# tiny_counter abstract. Synthetic test fixture.
VERSION 5.8 ;
BUSBITCHARS "[]" ;
DIVIDERCHAR "/" ;
UNITS
  DATABASE MICRONS 1000 ;
END UNITS
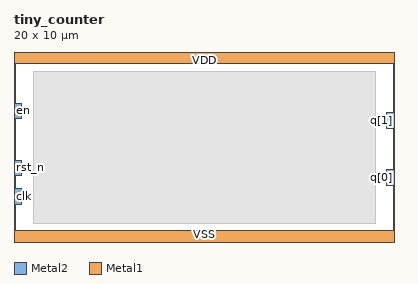
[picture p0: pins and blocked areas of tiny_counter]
MACRO tiny_counter
  CLASS BLOCK ;
  FOREIGN tiny_counter ;
  ORIGIN 0 0 ;
  SIZE 20 BY 10 ;
  PIN clk
    DIRECTION INPUT ;
    USE CLOCK ;
    PORT
      LAYER Metal2 ;
        RECT 0 2 0.4 2.8 ;
    END
  END clk
  PIN rst_n
    DIRECTION INPUT ;
    USE SIGNAL ;
    PORT
      LAYER Metal2 ;
        RECT 0 3.5 0.4 4.3 ;
    END
  END rst_n
  PIN en
    DIRECTION INPUT ;
    USE SIGNAL ;
    PORT
      LAYER Metal2 ;
        RECT 0 6.5 0.4 7.3 ;
    END
  END en
  PIN q[0]
    DIRECTION OUTPUT ;
    USE SIGNAL ;
    PORT
      LAYER Metal2 ;
        RECT 19.6 3 20 3.8 ;
    END
  END q[0]
  PIN q[1]
    DIRECTION OUTPUT ;
    USE SIGNAL ;
    PORT
      LAYER Metal2 ;
        RECT 19.6 6 20 6.8 ;
    END
  END q[1]
  PIN VDD
    DIRECTION INOUT ;
    USE POWER ;
    PORT
      LAYER Metal1 ;
        RECT 0 9.4 20 10 ;
    END
  END VDD
  PIN VSS
    DIRECTION INOUT ;
    USE GROUND ;
    PORT
      LAYER Metal1 ;
        RECT 0 0 20 0.6 ;
    END
  END VSS
  OBS
    LAYER Metal1 ;
      RECT 1 1 19 9 ;
    LAYER Metal2 ;
      RECT 1 1 19 9 ;
  END
END tiny_counter
END LIBRARY
